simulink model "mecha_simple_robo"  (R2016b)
settings: Solver=ode45  StartTime=0.0  StopTime=t(end)  RelTol=1e-3  EnableMultiTasking=on
InitFcn:
  | clear all;
  | 
  | y=robot_parameter;
  | 
  | l2=y.l2;%l2 リンク2長[mm]
  | l3=y.l3;%l3 リンク3長[mm]
  | w=y.w;%w ロボットの幅[mm]
  | s=y.s;%s ロボットの足裏サイズ(奥行き、幅は等しい)[mm]
  | M_s=y.M_s;%M_s RS,LS　質量[kg]
  | Ix_s=y.Ix_s;%Ix_s RS,LS xx軸回りイナーシャ[Kg.m^2]
  | Iy_s=y.Iy_s;%Iy_s RS,LS yy軸回りイナーシャ[Kg.m^2]
  | Iz_s=y.Iz_s;%Iz_s RS,LS zz軸回りイナーシャ[Kg.m^2]
  | M_l23=y.M_l23;%M_l23 R3,R2,L3,L2 質量[kg]
  | Ix_l23=y.Ix_l23;%Ix_l23 R3,R2,L3,L2 xx軸回りイナーシャ[Kg.m^2]
  | Iy_l23=y.Iy_l23;%Iy_l23 R3,R2,L3,L2 yy軸回りイナーシャ[Kg.m^2]
  | Iz_l23=y.Iz_l23;%Iz_l23 R3,R2,L3,L2 zz軸回りイナーシャ[Kg.m^2]
  | M_w=y.M_w;%M_w W 質量[kg]
  | Ix_w=y.Ix_w;%Ix_w W xx軸回りイナーシャ[Kg.m^2]
  | Iy_w=y.Iy_w;%Iy_w W yy軸回りイナーシャ[Kg.m^2]
  | Iz_w=y.Iz_w;%Iz_w W zz軸回りイナーシャ[Kg.m^2]
  | 
  | %関節角度データ読み込み
  | load('theta_data');
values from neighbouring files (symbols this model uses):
  N = walk_para.N    [main.m]    (also in walk_parameter.m = 5; initialize_para.m = 100)
undefined symbols (not defined in the file or in its folder): cm, g, kg, m, rad
libraries: mblibv1 x24

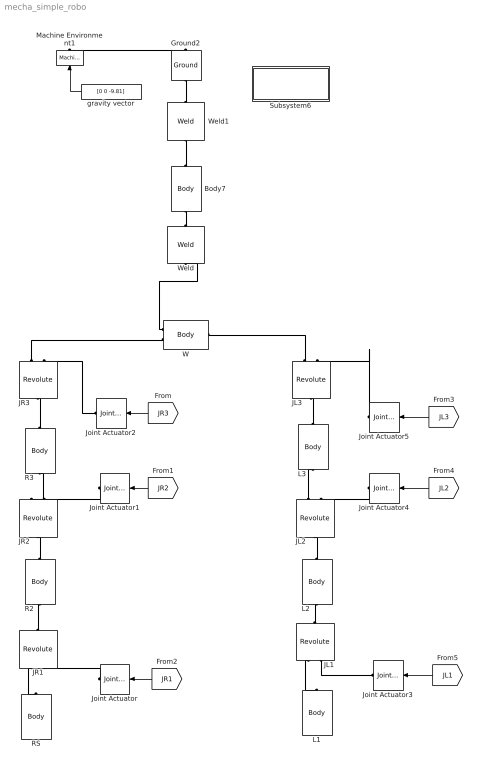
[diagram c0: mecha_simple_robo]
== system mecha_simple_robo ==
  Body7 : mblibv1/Bodies/Body  LConnTagsString=CS1  RConnTagsString=CS2  UpdateFromCAD=off  DialogClass=MechanicalBodyBlock  Mass=1  MassUnits=g  InertiaUnits=g*cm^2  Inertia=diag([,0.05,0.05,0.01])  Shape=Cylinder  ShapeDims=[1 1]  ShapeUnits=m  ShapeUse=false  Density=1  DensityUnits=kg/m^3  DensityUse=false  GraphicsMode=MACHINE_DEFAULT  BodyColorSelMode=MACHINE_DEFAULT  BodyColor=[1;0;0]  AttachedToCS=CG  CG=Left$CG$[0 0 50]$CS1$CS1$mm$[0 0 0]$Euler X-Y-Z$deg$WORLD$false  WorkingFrames=Left$CS1$[0 0 0]$Adjoining$Adjoining$mm$[0 0 0]$Euler X-Y-Z$deg$WORLD$true#Right$CS2$[0 0 100]$CS1$CS1$mm$[0 0 0]$Euler X-Y-Z$deg$WORLD$true  CGPos=[0 0 50]  CGRot=[0 0 0]  CS0Pos=[]  CS0Rot=[]  CS1Pos=[0 0 0]  CS1Rot=[0 0 0]  CS2Pos=[0 0 100]  CS2Rot=[0 0 0]  CS3Pos=[]  CS3Rot=[]  CS4Pos=[]  CS4Rot=[]  CS5Pos=[]  CS5Rot=[]  CS6Pos=[]  CS6Rot=[]  CS7Pos=[]  CS7Rot=[]  CS8Pos=[]  CS8Rot=[]  CS9Pos=[]  CS9Rot=[]  CS10Pos=[]  CS10Rot=[]  CS11Pos=[]  CS11Rot=[]  CS12Pos=[]  CS12Rot=[]  CS13Pos=[]  CS13Rot=[]  CS14Pos=[]  CS14Rot=[]  CS15Pos=[]  CS15Rot=[]  CS16Pos=[]  CS16Rot=[]  CS17Pos=[]  CS17Rot=[]  CS18Pos=[]  CS18Rot=[]  CS19Pos=[]  CS19Rot=[]  CS20Pos=[]  CS20Rot=[]
  Ground2 : mblibv1/Bodies/Ground  UpdateFromCAD=off  LeftPortType=env  RightPortType=workingframe  PhysicalDomain=Mechanical  DialogClass=GroundBlock  CoordPosition=[0 0 300]  CoordPositionUnits=mm  StateVectorMgrId=-1  MachineId=[0 0]  ShowEnvPort=on  ParameterChecksum=[3795268490, 2728262519, 337070678, 4082451969]  TopologyChecksum=[2413265805, 4068165552, 404330239, 870689057]
  JL1 : mblibv1/Joints/Revolute  LConnTagsString=__newl0|SA1  RConnTagsString=__newr0  UpdateFromCAD=off  NumSAPorts=1  CutJoint=off  MarkAsCut=off  Primitives=revolute  PrimitiveProps=R1$World$[0 1 0]$revolute  DialogClass=JointBlock  R1Axis=[0 1 0]
  JL2 : mblibv1/Joints/Revolute  LConnTagsString=__newl0|SA1  RConnTagsString=__newr0  UpdateFromCAD=off  NumSAPorts=1  CutJoint=off  MarkAsCut=off  Primitives=revolute  PrimitiveProps=R1$World$[0 1 0]$revolute  DialogClass=JointBlock  R1Axis=[0 1 0]
  JL3 : mblibv1/Joints/Revolute  LConnTagsString=__newl0|SA1  RConnTagsString=__newr0  UpdateFromCAD=off  NumSAPorts=1  CutJoint=off  MarkAsCut=off  Primitives=revolute  PrimitiveProps=R1$World$[0 1 0]$revolute  DialogClass=JointBlock  R1Axis=[0 1 0]
  JR1 : mblibv1/Joints/Revolute  LConnTagsString=__newl0|SA1  RConnTagsString=__newr0  UpdateFromCAD=off  NumSAPorts=1  CutJoint=off  MarkAsCut=off  Primitives=revolute  PrimitiveProps=R1$World$[0 1 0]$revolute  DialogClass=JointBlock  R1Axis=[0 1 0]
  JR2 : mblibv1/Joints/Revolute  LConnTagsString=__newl0|SA1  RConnTagsString=__newr0  UpdateFromCAD=off  NumSAPorts=1  CutJoint=off  MarkAsCut=off  Primitives=revolute  PrimitiveProps=R1$World$[0 1 0]$revolute  DialogClass=JointBlock  R1Axis=[0 1 0]
  JR3 : mblibv1/Joints/Revolute  LConnTagsString=__newl0|SA1  RConnTagsString=__newr0  UpdateFromCAD=off  NumSAPorts=1  CutJoint=off  MarkAsCut=off  Primitives=revolute  PrimitiveProps=R1$World$[0 1 0]$revolute  DialogClass=JointBlock  R1Axis=[0 1 0]
  Joint Actuator{,1..5} (6 alike) : mblibv1/Sensors &  Actuators/Joint Actuator  UpdateFromCAD=off  PhysicalDomain=Mechanical  PortType=blob  ActuationStyle=Motion  AngleUnits=rad  ArcVelocityUnits=rad/s  ArcAccelerationUnits=rad/s^2  CoordPositionUnits=m  VelocityUnits=m/s  AccelerationUnits=m/s^2  ForceUnits=N  TorqueUnits=N*m  ActiveIO=on  Width=3  DialogClass=MechanicalActuatorBlock  Primitive=R1  ReferenceFrame=Absolute (World)
  L1 : mblibv1/Bodies/Body  LConnTagsString=CS1  UpdateFromCAD=off  DialogClass=MechanicalBodyBlock  Mass=M_s  MassUnits=kg  InertiaUnits=kg*m^2  Inertia=diag([Ix_s,Iy_s,Iz_s])  Shape=Cylinder  ShapeDims=[1 1]  ShapeUnits=m  ShapeUse=false  Density=1  DensityUnits=kg/m^3  DensityUse=false  GraphicsMode=MACHINE_DEFAULT  BodyColorSelMode=MACHINE_DEFAULT  BodyColor=[1;0;0]  AttachedToCS=CG  CG=Left$CG$[0 0 0]$CS1$CS1$mm$[0 0 0]$Euler X-Y-Z$deg$WORLD$false  WorkingFrames=Left$CS1$[0 w/2 0]$World$World$mm$[0 0 0]$Euler X-Y-Z$deg$WORLD$true#Right$CS2$[s s 0]$CG$CG$mm$[0 0 0]$Euler X-Y-Z$deg$WORLD$false#Right$CS3$[-s s 0]$CG$CG$mm$[0 0 0]$Euler X-Y-Z$deg$WORLD$false#Right$CS4$[-s -s 0]$CG$CG$mm$[0 0 0]$Euler X-Y-Z$deg$WORLD$false#Right$CS5$[s -s 0]$CG$CG$mm$[0 0 0]$Euler X-Y-Z$deg$WORLD$false  CGPos=[0 0 0]  CGRot=[0 0 0]  CS0Pos=[]  CS0Rot=[]  CS1Pos=[0 w/2 0]  CS1Rot=[0 0 0]  CS2Pos=[s s 0]  CS2Rot=[0 0 0]  CS3Pos=[-s s 0]  CS3Rot=[0 0 0]  CS4Pos=[-s -s 0]  CS4Rot=[0 0 0]  CS5Pos=[s -s 0]  CS5Rot=[0 0 0]  CS6Pos=[]  CS6Rot=[]  CS7Pos=[]  CS7Rot=[]  CS8Pos=[]  CS8Rot=[]  CS9Pos=[]  CS9Rot=[]  CS10Pos=[]  CS10Rot=[]  CS11Pos=[]  CS11Rot=[]  CS12Pos=[]  CS12Rot=[]  CS13Pos=[]  CS13Rot=[]  CS14Pos=[]  CS14Rot=[]  CS15Pos=[]  CS15Rot=[]  CS16Pos=[]  CS16Rot=[]  CS17Pos=[]  CS17Rot=[]  CS18Pos=[]  CS18Rot=[]  CS19Pos=[]  CS19Rot=[]  CS20Pos=[]  CS20Rot=[]
  L2 : mblibv1/Bodies/Body  LConnTagsString=CS1  RConnTagsString=CS2  UpdateFromCAD=off  DialogClass=MechanicalBodyBlock  Mass=M_l23  MassUnits=kg  InertiaUnits=kg*m^2  Inertia=diag([Ix_l23,Iy_l23,Iz_l23])  Shape=Cylinder  ShapeDims=[1 1]  ShapeUnits=m  ShapeUse=false  Density=1  DensityUnits=kg/m^3  DensityUse=false  GraphicsMode=MACHINE_DEFAULT  BodyColorSelMode=MACHINE_DEFAULT  BodyColor=[1;0;0]  AttachedToCS=CG  CG=Left$CG$[0 0 l2/2]$CS1$CS1$mm$[0 0 0]$Euler X-Y-Z$deg$WORLD$false  WorkingFrames=Left$CS1$[0 0 0]$Adjoining$Adjoining$mm$[0 0 0]$Euler X-Y-Z$deg$WORLD$true#Right$CS2$[0 0 l2]$CS1$CS1$mm$[0 0 0]$Euler X-Y-Z$deg$WORLD$true  CGPos=[0 0 l2/2]  CGRot=[0 0 0]  CS0Pos=[]  CS0Rot=[]  CS1Pos=[0 0 0]  CS1Rot=[0 0 0]  CS2Pos=[0 0 l2]  CS2Rot=[0 0 0]  CS3Pos=[]  CS3Rot=[]  CS4Pos=[]  CS4Rot=[]  CS5Pos=[]  CS5Rot=[]  CS6Pos=[]  CS6Rot=[]  CS7Pos=[]  CS7Rot=[]  CS8Pos=[]  CS8Rot=[]  CS9Pos=[]  CS9Rot=[]  CS10Pos=[]  CS10Rot=[]  CS11Pos=[]  CS11Rot=[]  CS12Pos=[]  CS12Rot=[]  CS13Pos=[]  CS13Rot=[]  CS14Pos=[]  CS14Rot=[]  CS15Pos=[]  CS15Rot=[]  CS16Pos=[]  CS16Rot=[]  CS17Pos=[]  CS17Rot=[]  CS18Pos=[]  CS18Rot=[]  CS19Pos=[]  CS19Rot=[]  CS20Pos=[]  CS20Rot=[]
  L3 : mblibv1/Bodies/Body  LConnTagsString=CS1  RConnTagsString=CS2  UpdateFromCAD=off  DialogClass=MechanicalBodyBlock  Mass=M_l23  MassUnits=kg  InertiaUnits=kg*m^2  Inertia=diag([Ix_l23,Iy_l23,Iz_l23])  Shape=Cylinder  ShapeDims=[1 1]  ShapeUnits=m  ShapeUse=false  Density=1  DensityUnits=kg/m^3  DensityUse=false  GraphicsMode=MACHINE_DEFAULT  BodyColorSelMode=MACHINE_DEFAULT  BodyColor=[1;0;0]  AttachedToCS=CG  CG=Left$CG$[0 0 l3/2]$CS1$CS1$mm$[0 0 0]$Euler X-Y-Z$deg$WORLD$false  WorkingFrames=Left$CS1$[0 0 0]$Adjoining$Adjoining$mm$[0 0 0]$Euler X-Y-Z$deg$WORLD$true#Right$CS2$[0 0 l3]$CS1$CS1$mm$[0 0 0]$Euler X-Y-Z$deg$WORLD$true  CGPos=[0 0 l3/2]  CGRot=[0 0 0]  CS0Pos=[]  CS0Rot=[]  CS1Pos=[0 0 0]  CS1Rot=[0 0 0]  CS2Pos=[0 0 l3]  CS2Rot=[0 0 0]  CS3Pos=[]  CS3Rot=[]  CS4Pos=[]  CS4Rot=[]  CS5Pos=[]  CS5Rot=[]  CS6Pos=[]  CS6Rot=[]  CS7Pos=[]  CS7Rot=[]  CS8Pos=[]  CS8Rot=[]  CS9Pos=[]  CS9Rot=[]  CS10Pos=[]  CS10Rot=[]  CS11Pos=[]  CS11Rot=[]  CS12Pos=[]  CS12Rot=[]  CS13Pos=[]  CS13Rot=[]  CS14Pos=[]  CS14Rot=[]  CS15Pos=[]  CS15Rot=[]  CS16Pos=[]  CS16Rot=[]  CS17Pos=[]  CS17Rot=[]  CS18Pos=[]  CS18Rot=[]  CS19Pos=[]  CS19Rot=[]  CS20Pos=[]  CS20Rot=[]
  Machine Environment1 : mblibv1/Bodies/Machine Environment  Tag=Factory ground  PortType=env  PhysicalDomain=Mechanical  DialogTemplateClass=MECH.MachineEnvironment  SyncWhenCopied=off  Gravity=[0 0 9.81]  GravityUnits=m/s^2  GravityAsSignal=on  Dimensionality=Auto-detect  AnalysisType=Forward dynamics  LinearAssemblyTolerance=1e-3  LinearAssemblyToleranceUnits=m  AngularAssemblyTolerance=1e-3  AngularAssemblyToleranceUnits=rad  ConstraintSolverType=Stabilizing  ConstraintRelTolerance=1e-4  ConstraintAbsTolerance=1e-4  UseRobustSingularityHandling=off  RedundancyAnalysisToleranceType=Automatically select tolerance  RedundancyAnalysisTolerance=1e-14  StatePerturbationType=Fixed  PerturbationSize=1e-5  VisualizeMachine=on  BodyVisualizationType=Use model default body geometries  BodyColorSelMode=Use model default  DefaultBodyColor=[1 0 0]
  R2 : mblibv1/Bodies/Body  LConnTagsString=CS1  RConnTagsString=CS2  UpdateFromCAD=off  DialogClass=MechanicalBodyBlock  Mass=M_l23  MassUnits=kg  InertiaUnits=kg*m^2  Inertia=diag([Ix_l23,Iy_l23,Iz_l23])  Shape=Cylinder  ShapeDims=[1 1]  ShapeUnits=m  ShapeUse=false  Density=1  DensityUnits=kg/m^3  DensityUse=false  GraphicsMode=MACHINE_DEFAULT  BodyColorSelMode=MACHINE_DEFAULT  BodyColor=[1;0;0]  AttachedToCS=CG  CG=Left$CG$[0 0 l2/2]$CS1$CS1$mm$[0 0 0]$Euler X-Y-Z$deg$WORLD$false  WorkingFrames=Left$CS1$[0 0 0]$Adjoining$Adjoining$mm$[0 0 0]$Euler X-Y-Z$deg$Adjoining$true#Right$CS2$[0 0 l2]$CS1$CS1$mm$[0 0 0]$Euler X-Y-Z$deg$WORLD$true  CGPos=[0 0 l2/2]  CGRot=[0 0 0]  CS0Pos=[]  CS0Rot=[]  CS1Pos=[0 0 0]  CS1Rot=[0 0 0]  CS2Pos=[0 0 l2]  CS2Rot=[0 0 0]  CS3Pos=[]  CS3Rot=[]  CS4Pos=[]  CS4Rot=[]  CS5Pos=[]  CS5Rot=[]  CS6Pos=[]  CS6Rot=[]  CS7Pos=[]  CS7Rot=[]  CS8Pos=[]  CS8Rot=[]  CS9Pos=[]  CS9Rot=[]  CS10Pos=[]  CS10Rot=[]  CS11Pos=[]  CS11Rot=[]  CS12Pos=[]  CS12Rot=[]  CS13Pos=[]  CS13Rot=[]  CS14Pos=[]  CS14Rot=[]  CS15Pos=[]  CS15Rot=[]  CS16Pos=[]  CS16Rot=[]  CS17Pos=[]  CS17Rot=[]  CS18Pos=[]  CS18Rot=[]  CS19Pos=[]  CS19Rot=[]  CS20Pos=[]  CS20Rot=[]
  R3 : mblibv1/Bodies/Body  LConnTagsString=CS1  RConnTagsString=CS2  UpdateFromCAD=off  DialogClass=MechanicalBodyBlock  Mass=M_l23  MassUnits=kg  InertiaUnits=kg*m^2  Inertia=diag([Ix_l23,Iy_l23,Iz_l23])  Shape=Cylinder  ShapeDims=[1 1]  ShapeUnits=m  ShapeUse=false  Density=1  DensityUnits=kg/m^3  DensityUse=false  GraphicsMode=MACHINE_DEFAULT  BodyColorSelMode=MACHINE_DEFAULT  BodyColor=[1;0;0]  AttachedToCS=CG  CG=Left$CG$[0 0 l3/2]$CS1$CS1$mm$[0 0 0]$Euler X-Y-Z$deg$WORLD$false  WorkingFrames=Left$CS1$[0 0 0]$Adjoining$Adjoining$mm$[0 0 0]$Euler X-Y-Z$deg$WORLD$true#Right$CS2$[0 0 l3]$CS1$CS1$mm$[0 0 0]$Euler X-Y-Z$deg$WORLD$true  CGPos=[0 0 l3/2]  CGRot=[0 0 0]  CS0Pos=[]  CS0Rot=[]  CS1Pos=[0 0 0]  CS1Rot=[0 0 0]  CS2Pos=[0 0 l3]  CS2Rot=[0 0 0]  CS3Pos=[]  CS3Rot=[]  CS4Pos=[]  CS4Rot=[]  CS5Pos=[]  CS5Rot=[]  CS6Pos=[]  CS6Rot=[]  CS7Pos=[]  CS7Rot=[]  CS8Pos=[]  CS8Rot=[]  CS9Pos=[]  CS9Rot=[]  CS10Pos=[]  CS10Rot=[]  CS11Pos=[]  CS11Rot=[]  CS12Pos=[]  CS12Rot=[]  CS13Pos=[]  CS13Rot=[]  CS14Pos=[]  CS14Rot=[]  CS15Pos=[]  CS15Rot=[]  CS16Pos=[]  CS16Rot=[]  CS17Pos=[]  CS17Rot=[]  CS18Pos=[]  CS18Rot=[]  CS19Pos=[]  CS19Rot=[]  CS20Pos=[]  CS20Rot=[]
  RS : mblibv1/Bodies/Body  LConnTagsString=CS1  UpdateFromCAD=off  DialogClass=MechanicalBodyBlock  Mass=M_s  MassUnits=kg  InertiaUnits=kg*m^2  Inertia=diag([Ix_s,Iy_s,Iz_s])  Shape=Cylinder  ShapeDims=[1 1]  ShapeUnits=m  ShapeUse=false  Density=1  DensityUnits=kg/m^3  DensityUse=false  GraphicsMode=MACHINE_DEFAULT  BodyColorSelMode=MACHINE_DEFAULT  BodyColor=[1;0;0]  AttachedToCS=CG  CG=Left$CG$[0 0 0]$CS1$CS1$mm$[0 0 0]$Euler X-Y-Z$deg$WORLD$false  WorkingFrames=Left$CS1$[0 -w/2 0]$World$World$mm$[0 0 0]$Euler X-Y-Z$deg$WORLD$true#Right$CS2$[s s 0]$CG$CG$mm$[0 0 0]$Euler X-Y-Z$deg$WORLD$false#Right$CS3$[-s s 0]$CG$CG$mm$[0 0 0]$Euler X-Y-Z$deg$WORLD$false#Right$CS4$[-s -s 0]$CG$CG$mm$[0 0 0]$Euler X-Y-Z$deg$WORLD$false#Right$CS5$[s -s 0]$CG$CG$mm$[0 0 0]$Euler X-Y-Z$deg$WORLD$false  CGPos=[0 0 0]  CGRot=[0 0 0]  CS0Pos=[]  CS0Rot=[]  CS1Pos=[0 -w/2 0]  CS1Rot=[0 0 0]  CS2Pos=[s s 0]  CS2Rot=[0 0 0]  CS3Pos=[-s s 0]  CS3Rot=[0 0 0]  CS4Pos=[-s -s 0]  CS4Rot=[0 0 0]  CS5Pos=[s -s 0]  CS5Rot=[0 0 0]  CS6Pos=[]  CS6Rot=[]  CS7Pos=[]  CS7Rot=[]  CS8Pos=[]  CS8Rot=[]  CS9Pos=[]  CS9Rot=[]  CS10Pos=[]  CS10Rot=[]  CS11Pos=[]  CS11Rot=[]  CS12Pos=[]  CS12Rot=[]  CS13Pos=[]  CS13Rot=[]  CS14Pos=[]  CS14Rot=[]  CS15Pos=[]  CS15Rot=[]  CS16Pos=[]  CS16Rot=[]  CS17Pos=[]  CS17Rot=[]  CS18Pos=[]  CS18Rot=[]  CS19Pos=[]  CS19Rot=[]  CS20Pos=[]  CS20Rot=[]
  Subsystem6 : Subsystem
  W : mblibv1/Bodies/Body  LConnTagsString=CG|CS1  RConnTagsString=CS2  UpdateFromCAD=off  DialogClass=MechanicalBodyBlock  Mass=M_w  MassUnits=kg  InertiaUnits=kg*m^2  Inertia=diag([Ix_w,Iy_w,Iz_w])  Shape=Cylinder  ShapeDims=[1 1]  ShapeUnits=m  ShapeUse=false  Density=1  DensityUnits=kg/m^3  DensityUse=false  GraphicsMode=MACHINE_DEFAULT  BodyColorSelMode=MACHINE_DEFAULT  BodyColor=[1;0;0]  AttachedToCS=CG  CG=Left$CG$[0 w/2 0]$CS1$CS1$mm$[0 0 0]$Euler X-Y-Z$deg$WORLD$true  WorkingFrames=Left$CS1$[0 0 0]$Adjoining$Adjoining$mm$[0 0 0]$Euler X-Y-Z$deg$WORLD$true#Right$CS2$[0 w 0]$CS1$CS1$mm$[0 0 0]$Euler X-Y-Z$deg$WORLD$true  CGPos=[0 w/2 0]  CGRot=[0 0 0]  CS0Pos=[]  CS0Rot=[]  CS1Pos=[0 0 0]  CS1Rot=[0 0 0]  CS2Pos=[0 w 0]  CS2Rot=[0 0 0]  CS3Pos=[]  CS3Rot=[]  CS4Pos=[]  CS4Rot=[]  CS5Pos=[]  CS5Rot=[]  CS6Pos=[]  CS6Rot=[]  CS7Pos=[]  CS7Rot=[]  CS8Pos=[]  CS8Rot=[]  CS9Pos=[]  CS9Rot=[]  CS10Pos=[]  CS10Rot=[]  CS11Pos=[]  CS11Rot=[]  CS12Pos=[]  CS12Rot=[]  CS13Pos=[]  CS13Rot=[]  CS14Pos=[]  CS14Rot=[]  CS15Pos=[]  CS15Rot=[]  CS16Pos=[]  CS16Rot=[]  CS17Pos=[]  CS17Rot=[]  CS18Pos=[]  CS18Rot=[]  CS19Pos=[]  CS19Rot=[]  CS20Pos=[]  CS20Rot=[]
  Weld : mblibv1/Joints/Weld  LConnTagsString=__newl0  RConnTagsString=__newr0  UpdateFromCAD=off  NumSAPorts=0  CutJoint=off  MarkAsCut=off  Primitives=weld  PrimitiveProps=W$World$[0 0 0]$weld  DialogClass=JointBlock  WAxis=[0 0 0]
  Weld1 : mblibv1/Joints/Weld  LConnTagsString=__newl0  RConnTagsString=__newr0  UpdateFromCAD=off  NumSAPorts=0  CutJoint=off  MarkAsCut=off  Primitives=weld  PrimitiveProps=W$World$[0 0 0]$weld  DialogClass=JointBlock  WAxis=[0 0 0]
  gravity vector : Constant  Value=[0 0 -9.81]
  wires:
  gravity vector/1 -> Machine Environment1/1
  [JR3] -> Joint Actuator2/1
  [JR2] -> Joint Actuator1/1
  [JR1] -> Joint Actuator/1
  [JL3] -> Joint Actuator5/1
  [JL2] -> Joint Actuator4/1
  [JL1] -> Joint Actuator3/1
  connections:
  Joint Actuator/RConn1 -- JR1/LConn2
  JR1/RConn1 -- R2/LConn1
  Machine Environment1/RConn1 -- Ground2/LConn1
  R2/RConn1 -- JR2/RConn1
  Joint Actuator1/RConn1 -- JR2/LConn2
  JR2/LConn1 -- R3/LConn1
  R3/RConn1 -- JR3/RConn1
  JR3/LConn2 -- Joint Actuator2/RConn1
  L1/LConn1 -- JL1/LConn1
  JL1/LConn2 -- Joint Actuator3/RConn1
  JL1/RConn1 -- L2/LConn1
  L2/RConn1 -- JL2/RConn1
  Joint Actuator4/RConn1 -- JL2/LConn2
  JL2/LConn1 -- L3/LConn1
  L3/RConn1 -- JL3/RConn1
  Weld/RConn1 -- Body7/LConn1
  Ground2/RConn1 -- Weld1/LConn1
  Weld1/RConn1 -- Body7/RConn1
  JL3/LConn1 -- W/RConn1
  Joint Actuator5/RConn1 -- JL3/LConn2
  RS/LConn1 -- JR1/LConn1
  JR3/LConn1 -- W/LConn2
  W/LConn1 -- Weld/LConn1

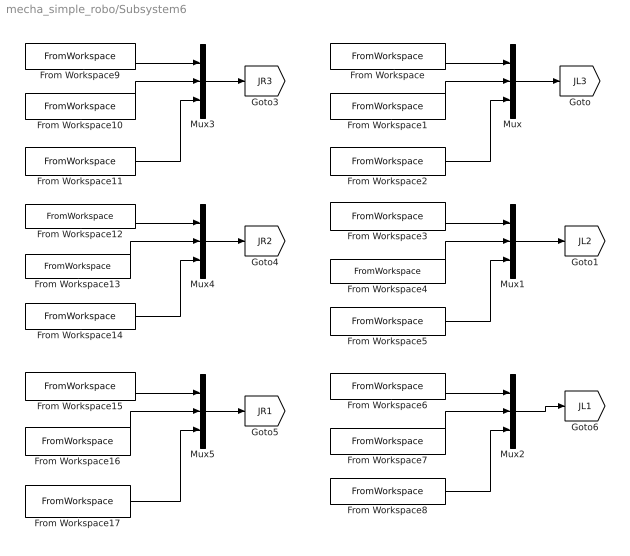
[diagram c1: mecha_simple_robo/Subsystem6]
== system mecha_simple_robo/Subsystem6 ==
  From Workspace : FromWorkspace  VariableName=[t' JL3.theta']  SampleTime=0
  From Workspace1 : FromWorkspace  VariableName=[t' JL3.thetadot']  SampleTime=0
  From Workspace10 : FromWorkspace  VariableName=[t' JR3.thetadot']  SampleTime=0
  From Workspace11 : FromWorkspace  VariableName=[t' JR3.theta2dot']  SampleTime=0
  From Workspace12 : FromWorkspace  VariableName=[t' JR2.theta']  SampleTime=0
  From Workspace13 : FromWorkspace  VariableName=[t' JR2.thetadot']  SampleTime=0
  From Workspace14 : FromWorkspace  VariableName=[t' JR2.theta2dot']  SampleTime=0
  From Workspace15 : FromWorkspace  VariableName=[t' JR1.theta']  SampleTime=0
  From Workspace16 : FromWorkspace  VariableName=[t' JR1.thetadot']  SampleTime=0
  From Workspace17 : FromWorkspace  VariableName=[t' JR1.theta2dot']  SampleTime=0
  From Workspace2 : FromWorkspace  VariableName=[t' JL3.theta2dot']  SampleTime=0
  From Workspace3 : FromWorkspace  VariableName=[t' JL2.theta']  SampleTime=0
  From Workspace4 : FromWorkspace  VariableName=[t' JL2.thetadot']  SampleTime=0
  From Workspace5 : FromWorkspace  VariableName=[t' JL2.theta2dot']  SampleTime=0
  From Workspace6 : FromWorkspace  VariableName=[t' JL1.theta']  SampleTime=0
  From Workspace7 : FromWorkspace  VariableName=[t' JL1.thetadot']  SampleTime=0
  From Workspace8 : FromWorkspace  VariableName=[t' JL1.theta2dot']  SampleTime=0
  From Workspace9 : FromWorkspace  VariableName=[t' JR3.theta']  SampleTime=0
  Mux{,1..5} (6 alike) : Mux  Inputs=3
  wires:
  From Workspace/1 -> Mux/1
  From Workspace1/1 -> Mux/2
  From Workspace2/1 -> Mux/3
  Mux/1 -> [JL3]
  From Workspace3/1 -> Mux1/1
  From Workspace4/1 -> Mux1/2
  From Workspace5/1 -> Mux1/3
  From Workspace6/1 -> Mux2/1
  From Workspace7/1 -> Mux2/2
  From Workspace8/1 -> Mux2/3
  Mux2/1 -> [JL1]
  From Workspace9/1 -> Mux3/1
  From Workspace10/1 -> Mux3/2
  From Workspace11/1 -> Mux3/3
  From Workspace12/1 -> Mux4/1
  From Workspace13/1 -> Mux4/2
  From Workspace14/1 -> Mux4/3
  From Workspace15/1 -> Mux5/1
  From Workspace16/1 -> Mux5/2
  From Workspace17/1 -> Mux5/3
  Mux1/1 -> [JL2]
  Mux3/1 -> [JR3]
  Mux4/1 -> [JR2]
  Mux5/1 -> [JR1]
